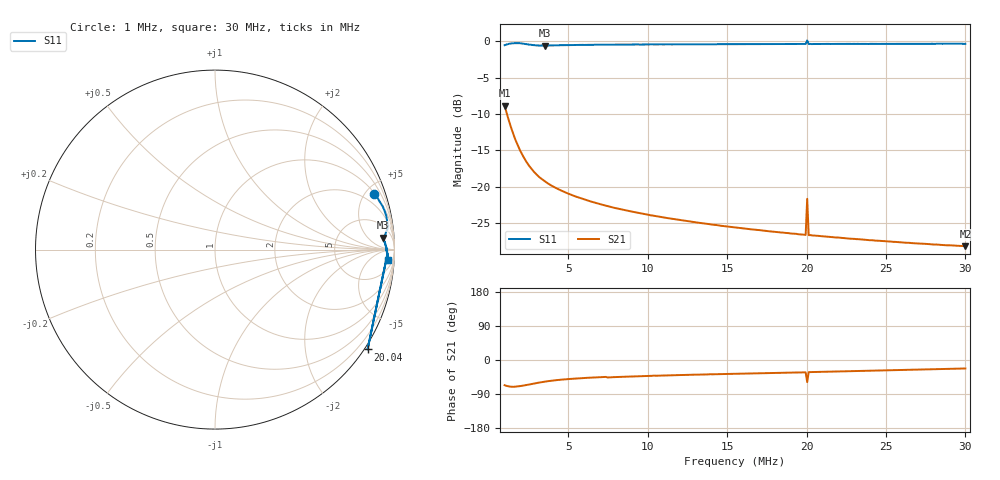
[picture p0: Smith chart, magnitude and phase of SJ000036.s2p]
!File created by NanoVNA-F V2
# Hz S RI R 50
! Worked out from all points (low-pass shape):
!   301 points, 1 MHz to 30 MHz, reference 50 ohm
!   highest |S21| = -8.86 dB at 1 MHz (marker M1); lowest = -28.2 dB at 30 MHz (marker M2)
!   |S21| within 3 dB of the highest: start of sweep to 1.405 MHz
!   lowest |S11| = -0.6 dB at 3.513 MHz (marker M3), VSWR 30.32, Z = 700 + j755 ohm
!   |S11| at or under -10 dB: nowhere
!   S12 and S22 are empty: the file has one direction only
!   S11 on the Smith chart (normalised r, x): 1 MHz: 1.03, +5.68; 20.04 MHz: -0.10, -3.35; 30 MHz: 14, -24
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1000000  0.8886 0.3124  0.144 -0.3306  0 0  0 0
1193332  0.9194 0.2635  0.1083 -0.2832  0 0  0 0
1386664  0.9431 0.2194  0.0866 -0.2439  0 0  0 0
1676662  0.9577 0.1687  0.0709 -0.1982  0 0  0 0
2063326  0.9617 0.1187  0.0625 -0.1578  0 0  0 0
2353324  0.9515 0.0942  0.06 -0.1364  0 0  0 0
2739988  0.9422 0.0748  0.0591 -0.1163  0 0  0 0
3029986  0.9354 0.0698  0.0591 -0.1048  0 0  0 0
3513316  0.9338 0.0667  0.0591 -0.0913  0 0  0 0
4383310  0.9394 0.0569  0.058 -0.0762  0 0  0 0
5349970  0.9436 0.0463  0.0562 -0.0653  0 0  0 0
5833300  0.9459 0.0409  0.0553 -0.0615  0 0  0 0
7863286  0.9513 0.0255  0.0503 -0.0508  0 0  0 0
1.06666e7  0.9537 0.00923  0.0466 -0.0409  0 0  0 0
1.259992e7  0.9559 -0.000296  0.0446 -0.0363  0 0  0 0
1.54999e7  0.9583 -0.0115  0.0421 -0.0311  0 0  0 0
1.994654e7  0.9606 -0.0268  0.0391 -0.025  0 0  0 0
2.00432e7  0.8499 -0.5564  0.0432 -0.0701  0 0  0 0
2.013987e7  0.9591 -0.0298  0.0392 -0.0245  0 0  0 0
2.03332e7  0.9583 -0.0274  0.0391 -0.0242  0 0  0 0
2.51665e7  0.9613 -0.0439  0.0372 -0.0191  0 0  0 0
2.99998e7  0.9613 -0.0596  0.0359 -0.0148  0 0  0 0
